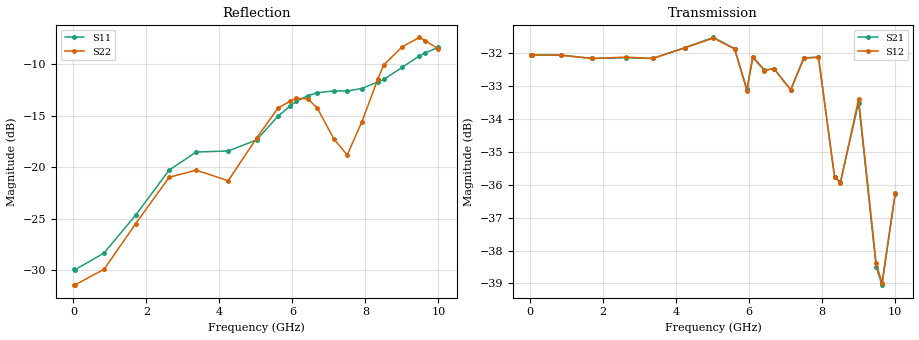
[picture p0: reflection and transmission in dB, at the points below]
! Integrated Device Technology
! Corporate Headquarters
! 6024 Silver Creek Valley Road
! San Jose, CA 95138  USA
! Phone:  1-408-284-8200
! Toll Free:  1-800-223-1366
! Webpage:  http://www.idt.com/
! Timing and RF Division
! 515 Groton Road, Suite 102
! Westford, MA 01886-6024
! Device:  F1958
! Description: 7-bit 0.25 dB Digital Step Attenuator
! Frequency:  0.001 -  6.000 GHz
! Package:  4x4 mm Thin QFN Plastic Package: 24 pin
! Ports:  2 RF, 12 DC
!  Pin  1  = D0
!  Pin  2  = VDD
!  Pin  3  = VMODE
!  Pin  4  = GND
!  Pin  5  = RF1  =  Port 1
!  Pin  6  = GND
!  Pin  7  = GND
!  Pin  8  = GND
!  Pin  9  = GND
!  Pin 10  = GND
!  Pin 11  = GND
!  Pin 12  = GND
!  Pin 13  = GND
!  Pin 14  = RF2  =  Port 2
!  Pin 15  = GND
!  Pin 16  = LE
!  Pin 17  = CLK
!  Pin 18  = DATA
!  Pin 19  = D6
!  Pin 20  = D5
!  Pin 21  = D4
!  Pin 22  = D3
!  Pin 23  = D2
!  Pin 24  = D1
! State:  125
! Atten State:  31.25 dB
! Voltage:  +3.30 Volts
! Current:  0.259 mA
! Data:  The device was measured on a F1958 evaluation board which has
!  individual transmission lines to the RF pins.  Data was collected
!  using a calibrated network analyzer.  The evaluation board was
!  de-embedded using Automatic Fixture Removal (AFR).
!  The reference plane is the edge of the package pin.
! Misc:
!  Action Tracker AT0419
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# GHz S dB R 50
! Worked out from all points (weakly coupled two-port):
!   500 points, 20 MHz to 10 GHz, reference 50 ohm
!   highest |S21| = -31.52 dB at 5.02 GHz (marker M1); lowest = -39.0 dB at 9.64 GHz (marker M2)
!   lowest |S11| = -29.9 dB at 40 MHz (marker M3), VSWR 1.07, Z = 46.9 - j0.0446 ohm
!   |S11| at or under -10 dB: start of sweep to 9.124 GHz
!   |S22| runs from -31.6 to -7.4 dB; largest |S21 - S12| = 0.00033
!   S11 on the Smith chart (normalised r, x): 20 MHz: 0.94, -0.00; 6.42 GHz: 0.67, +0.17; 10 GHz: 0.67, +0.59
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0.02  -29.89 -178.9  -32.07 -0.1  -32.07 -0.1  -31.43 -179.0
0.04  -29.94 -179.1  -32.05 -0.3  -32.05 -0.3  -31.41 -178.5
0.84  -28.31 171.3  -32.06 -8.7  -32.06 -8.6  -29.89 172.7
1.7  -24.66 171.2  -32.16 -17.1  -32.16 -17.1  -25.49 171.4
2.62  -20.28 177.0  -32.14 -26.4  -32.12 -26.3  -20.97 -179.9
3.36  -18.52 -175.8  -32.16 -34.5  -32.16 -34.5  -20.28 -170.2
4.24  -18.42 -179.3  -31.83 -43.6  -31.84 -43.6  -21.30 168.1
5.02  -17.34 160.6  -31.52 -53.4  -31.54 -53.4  -17.16 138.0
5.6  -15.06 150.6  -31.86 -61.9  -31.87 -61.9  -14.27 139.8
5.94  -14.05 148.2  -33.10 -65.1  -33.14 -65.0  -13.58 148.1
6.1  -13.61 148.4  -32.11 -64.9  -32.13 -64.8  -13.31 149.8
6.42  -13.05 147.4  -32.51 -70.4  -32.53 -70.4  -13.36 156.4
6.68  -12.77 146.5  -32.47 -72.9  -32.47 -72.8  -14.25 156.8
7.14  -12.59 142.6  -33.11 -77.6  -33.12 -77.4  -17.29 150.6
7.5  -12.60 138.0  -32.14 -81.1  -32.15 -81.0  -18.80 118.7
7.9  -12.36 128.7  -32.12 -98.1  -32.13 -98.1  -15.61 88.8
8.34  -11.71 118.7  -35.75 -103.0  -35.76 -103.1  -11.43 83.7
8.5  -11.48 115.3  -35.93 -93.6  -35.94 -93.8  -10.08 87.3
9  -10.32 108.3  -33.50 -102.1  -33.39 -102.1  -8.33 97.2
9.48  -9.19 101.7  -38.49 -107.5  -38.39 -107.4  -7.40 107.3
9.64  -8.89 101.1  -39.05 -94.3  -38.98 -94.0  -7.73 110.3
10  -8.37 99.6  -36.29 -76.7  -36.26 -76.6  -8.51 113.6
